VERSION 5.7 ;
BUSBITCHARS "[]" ;
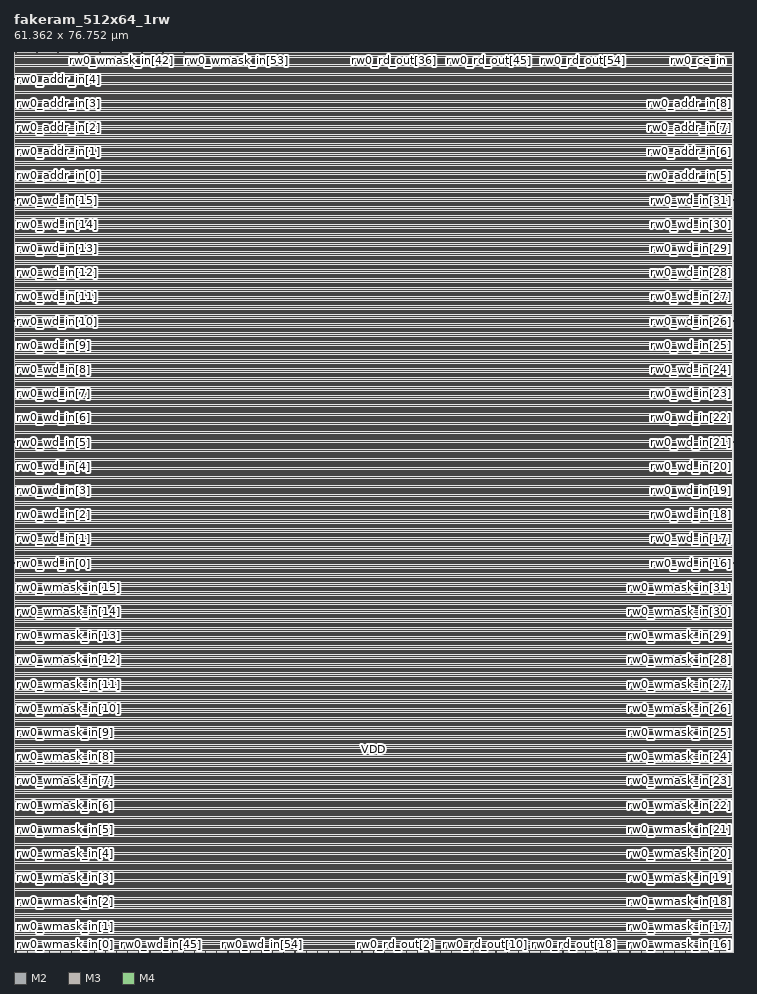
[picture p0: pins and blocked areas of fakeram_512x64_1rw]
MACRO fakeram_512x64_1rw
  FOREIGN fakeram_512x64_1rw 0 0 ;
  SYMMETRY X Y R90 ;
  SIZE 61.362 BY 76.752 ;
  CLASS BLOCK ;
  PIN rw0_wmask_in[0]
    DIRECTION INPUT ;
    USE SIGNAL ;
    SHAPE ABUTMENT ;
    PORT
      LAYER M2 ;
      RECT 0.000 0.138 0.036 0.150 ;
    END
  END rw0_wmask_in[0]
  PIN rw0_wmask_in[1]
    DIRECTION INPUT ;
    USE SIGNAL ;
    SHAPE ABUTMENT ;
    PORT
      LAYER M2 ;
      RECT 0.000 2.202 0.036 2.214 ;
    END
  END rw0_wmask_in[1]
  PIN rw0_wmask_in[2]
    DIRECTION INPUT ;
    USE SIGNAL ;
    SHAPE ABUTMENT ;
    PORT
      LAYER M2 ;
      RECT 0.000 4.266 0.036 4.278 ;
    END
  END rw0_wmask_in[2]
  PIN rw0_wmask_in[3]
    DIRECTION INPUT ;
    USE SIGNAL ;
    SHAPE ABUTMENT ;
    PORT
      LAYER M2 ;
      RECT 0.000 6.330 0.036 6.342 ;
    END
  END rw0_wmask_in[3]
  PIN rw0_wmask_in[4]
    DIRECTION INPUT ;
    USE SIGNAL ;
    SHAPE ABUTMENT ;
    PORT
      LAYER M2 ;
      RECT 0.000 8.394 0.036 8.406 ;
    END
  END rw0_wmask_in[4]
  PIN rw0_wmask_in[5]
    DIRECTION INPUT ;
    USE SIGNAL ;
    SHAPE ABUTMENT ;
    PORT
      LAYER M2 ;
      RECT 0.000 10.458 0.036 10.470 ;
    END
  END rw0_wmask_in[5]
  PIN rw0_wmask_in[6]
    DIRECTION INPUT ;
    USE SIGNAL ;
    SHAPE ABUTMENT ;
    PORT
      LAYER M2 ;
      RECT 0.000 12.522 0.036 12.534 ;
    END
  END rw0_wmask_in[6]
  PIN rw0_wmask_in[7]
    DIRECTION INPUT ;
    USE SIGNAL ;
    SHAPE ABUTMENT ;
    PORT
      LAYER M2 ;
      RECT 0.000 14.586 0.036 14.598 ;
    END
  END rw0_wmask_in[7]
  PIN rw0_wmask_in[8]
    DIRECTION INPUT ;
    USE SIGNAL ;
    SHAPE ABUTMENT ;
    PORT
      LAYER M2 ;
      RECT 0.000 16.650 0.036 16.662 ;
    END
  END rw0_wmask_in[8]
  PIN rw0_wmask_in[9]
    DIRECTION INPUT ;
    USE SIGNAL ;
    SHAPE ABUTMENT ;
    PORT
      LAYER M2 ;
      RECT 0.000 18.714 0.036 18.726 ;
    END
  END rw0_wmask_in[9]
  PIN rw0_wmask_in[10]
    DIRECTION INPUT ;
    USE SIGNAL ;
    SHAPE ABUTMENT ;
    PORT
      LAYER M2 ;
      RECT 0.000 20.778 0.036 20.790 ;
    END
  END rw0_wmask_in[10]
  PIN rw0_wmask_in[11]
    DIRECTION INPUT ;
    USE SIGNAL ;
    SHAPE ABUTMENT ;
    PORT
      LAYER M2 ;
      RECT 0.000 22.842 0.036 22.854 ;
    END
  END rw0_wmask_in[11]
  PIN rw0_wmask_in[12]
    DIRECTION INPUT ;
    USE SIGNAL ;
    SHAPE ABUTMENT ;
    PORT
      LAYER M2 ;
      RECT 0.000 24.906 0.036 24.918 ;
    END
  END rw0_wmask_in[12]
  PIN rw0_wmask_in[13]
    DIRECTION INPUT ;
    USE SIGNAL ;
    SHAPE ABUTMENT ;
    PORT
      LAYER M2 ;
      RECT 0.000 26.970 0.036 26.982 ;
    END
  END rw0_wmask_in[13]
  PIN rw0_wmask_in[14]
    DIRECTION INPUT ;
    USE SIGNAL ;
    SHAPE ABUTMENT ;
    PORT
      LAYER M2 ;
      RECT 0.000 29.034 0.036 29.046 ;
    END
  END rw0_wmask_in[14]
  PIN rw0_wmask_in[15]
    DIRECTION INPUT ;
    USE SIGNAL ;
    SHAPE ABUTMENT ;
    PORT
      LAYER M2 ;
      RECT 0.000 31.098 0.036 31.110 ;
    END
  END rw0_wmask_in[15]
  PIN rw0_wmask_in[16]
    DIRECTION INPUT ;
    USE SIGNAL ;
    SHAPE ABUTMENT ;
    PORT
      LAYER M2 ;
      RECT 61.326 0.138 61.362 0.150 ;
    END
  END rw0_wmask_in[16]
  PIN rw0_wmask_in[17]
    DIRECTION INPUT ;
    USE SIGNAL ;
    SHAPE ABUTMENT ;
    PORT
      LAYER M2 ;
      RECT 61.326 2.202 61.362 2.214 ;
    END
  END rw0_wmask_in[17]
  PIN rw0_wmask_in[18]
    DIRECTION INPUT ;
    USE SIGNAL ;
    SHAPE ABUTMENT ;
    PORT
      LAYER M2 ;
      RECT 61.326 4.266 61.362 4.278 ;
    END
  END rw0_wmask_in[18]
  PIN rw0_wmask_in[19]
    DIRECTION INPUT ;
    USE SIGNAL ;
    SHAPE ABUTMENT ;
    PORT
      LAYER M2 ;
      RECT 61.326 6.330 61.362 6.342 ;
    END
  END rw0_wmask_in[19]
  PIN rw0_wmask_in[20]
    DIRECTION INPUT ;
    USE SIGNAL ;
    SHAPE ABUTMENT ;
    PORT
      LAYER M2 ;
      RECT 61.326 8.394 61.362 8.406 ;
    END
  END rw0_wmask_in[20]
  PIN rw0_wmask_in[21]
    DIRECTION INPUT ;
    USE SIGNAL ;
    SHAPE ABUTMENT ;
    PORT
      LAYER M2 ;
      RECT 61.326 10.458 61.362 10.470 ;
    END
  END rw0_wmask_in[21]
  PIN rw0_wmask_in[22]
    DIRECTION INPUT ;
    USE SIGNAL ;
    SHAPE ABUTMENT ;
    PORT
      LAYER M2 ;
      RECT 61.326 12.522 61.362 12.534 ;
    END
  END rw0_wmask_in[22]
  PIN rw0_wmask_in[23]
    DIRECTION INPUT ;
    USE SIGNAL ;
    SHAPE ABUTMENT ;
    PORT
      LAYER M2 ;
      RECT 61.326 14.586 61.362 14.598 ;
    END
  END rw0_wmask_in[23]
  PIN rw0_wmask_in[24]
    DIRECTION INPUT ;
    USE SIGNAL ;
    SHAPE ABUTMENT ;
    PORT
      LAYER M2 ;
      RECT 61.326 16.650 61.362 16.662 ;
    END
  END rw0_wmask_in[24]
  PIN rw0_wmask_in[25]
    DIRECTION INPUT ;
    USE SIGNAL ;
    SHAPE ABUTMENT ;
    PORT
      LAYER M2 ;
      RECT 61.326 18.714 61.362 18.726 ;
    END
  END rw0_wmask_in[25]
  PIN rw0_wmask_in[26]
    DIRECTION INPUT ;
    USE SIGNAL ;
    SHAPE ABUTMENT ;
    PORT
      LAYER M2 ;
      RECT 61.326 20.778 61.362 20.790 ;
    END
  END rw0_wmask_in[26]
  PIN rw0_wmask_in[27]
    DIRECTION INPUT ;
    USE SIGNAL ;
    SHAPE ABUTMENT ;
    PORT
      LAYER M2 ;
      RECT 61.326 22.842 61.362 22.854 ;
    END
  END rw0_wmask_in[27]
  PIN rw0_wmask_in[28]
    DIRECTION INPUT ;
    USE SIGNAL ;
    SHAPE ABUTMENT ;
    PORT
      LAYER M2 ;
      RECT 61.326 24.906 61.362 24.918 ;
    END
  END rw0_wmask_in[28]
  PIN rw0_wmask_in[29]
    DIRECTION INPUT ;
    USE SIGNAL ;
    SHAPE ABUTMENT ;
    PORT
      LAYER M2 ;
      RECT 61.326 26.970 61.362 26.982 ;
    END
  END rw0_wmask_in[29]
  PIN rw0_wmask_in[30]
    DIRECTION INPUT ;
    USE SIGNAL ;
    SHAPE ABUTMENT ;
    PORT
      LAYER M2 ;
      RECT 61.326 29.034 61.362 29.046 ;
    END
  END rw0_wmask_in[30]
  PIN rw0_wmask_in[31]
    DIRECTION INPUT ;
    USE SIGNAL ;
    SHAPE ABUTMENT ;
    PORT
      LAYER M2 ;
      RECT 61.326 31.098 61.362 31.110 ;
    END
  END rw0_wmask_in[31]
  PIN rw0_wmask_in[32]
    DIRECTION INPUT ;
    USE SIGNAL ;
    SHAPE ABUTMENT ;
    PORT
      LAYER M3 ;
      RECT 0.161 76.710 0.175 76.752 ;
    END
  END rw0_wmask_in[32]
  PIN rw0_wmask_in[33]
    DIRECTION INPUT ;
    USE SIGNAL ;
    SHAPE ABUTMENT ;
    PORT
      LAYER M3 ;
      RECT 1.057 76.710 1.071 76.752 ;
    END
  END rw0_wmask_in[33]
  PIN rw0_wmask_in[34]
    DIRECTION INPUT ;
    USE SIGNAL ;
    SHAPE ABUTMENT ;
    PORT
      LAYER M3 ;
      RECT 1.953 76.710 1.967 76.752 ;
    END
  END rw0_wmask_in[34]
  PIN rw0_wmask_in[35]
    DIRECTION INPUT ;
    USE SIGNAL ;
    SHAPE ABUTMENT ;
    PORT
      LAYER M3 ;
      RECT 2.849 76.710 2.863 76.752 ;
    END
  END rw0_wmask_in[35]
  PIN rw0_wmask_in[36]
    DIRECTION INPUT ;
    USE SIGNAL ;
    SHAPE ABUTMENT ;
    PORT
      LAYER M3 ;
      RECT 3.745 76.710 3.759 76.752 ;
    END
  END rw0_wmask_in[36]
  PIN rw0_wmask_in[37]
    DIRECTION INPUT ;
    USE SIGNAL ;
    SHAPE ABUTMENT ;
    PORT
      LAYER M3 ;
      RECT 4.641 76.710 4.655 76.752 ;
    END
  END rw0_wmask_in[37]
  PIN rw0_wmask_in[38]
    DIRECTION INPUT ;
    USE SIGNAL ;
    SHAPE ABUTMENT ;
    PORT
      LAYER M3 ;
      RECT 5.537 76.710 5.551 76.752 ;
    END
  END rw0_wmask_in[38]
  PIN rw0_wmask_in[39]
    DIRECTION INPUT ;
    USE SIGNAL ;
    SHAPE ABUTMENT ;
    PORT
      LAYER M3 ;
      RECT 6.433 76.710 6.447 76.752 ;
    END
  END rw0_wmask_in[39]
  PIN rw0_wmask_in[40]
    DIRECTION INPUT ;
    USE SIGNAL ;
    SHAPE ABUTMENT ;
    PORT
      LAYER M3 ;
      RECT 7.329 76.710 7.343 76.752 ;
    END
  END rw0_wmask_in[40]
  PIN rw0_wmask_in[41]
    DIRECTION INPUT ;
    USE SIGNAL ;
    SHAPE ABUTMENT ;
    PORT
      LAYER M3 ;
      RECT 8.225 76.710 8.239 76.752 ;
    END
  END rw0_wmask_in[41]
  PIN rw0_wmask_in[42]
    DIRECTION INPUT ;
    USE SIGNAL ;
    SHAPE ABUTMENT ;
    PORT
      LAYER M3 ;
      RECT 9.121 76.710 9.135 76.752 ;
    END
  END rw0_wmask_in[42]
  PIN rw0_wmask_in[43]
    DIRECTION INPUT ;
    USE SIGNAL ;
    SHAPE ABUTMENT ;
    PORT
      LAYER M3 ;
      RECT 10.017 76.710 10.031 76.752 ;
    END
  END rw0_wmask_in[43]
  PIN rw0_wmask_in[44]
    DIRECTION INPUT ;
    USE SIGNAL ;
    SHAPE ABUTMENT ;
    PORT
      LAYER M3 ;
      RECT 10.913 76.710 10.927 76.752 ;
    END
  END rw0_wmask_in[44]
  PIN rw0_wmask_in[45]
    DIRECTION INPUT ;
    USE SIGNAL ;
    SHAPE ABUTMENT ;
    PORT
      LAYER M3 ;
      RECT 11.809 76.710 11.823 76.752 ;
    END
  END rw0_wmask_in[45]
  PIN rw0_wmask_in[46]
    DIRECTION INPUT ;
    USE SIGNAL ;
    SHAPE ABUTMENT ;
    PORT
      LAYER M3 ;
      RECT 12.705 76.710 12.719 76.752 ;
    END
  END rw0_wmask_in[46]
  PIN rw0_wmask_in[47]
    DIRECTION INPUT ;
    USE SIGNAL ;
    SHAPE ABUTMENT ;
    PORT
      LAYER M3 ;
      RECT 13.601 76.710 13.615 76.752 ;
    END
  END rw0_wmask_in[47]
  PIN rw0_wmask_in[48]
    DIRECTION INPUT ;
    USE SIGNAL ;
    SHAPE ABUTMENT ;
    PORT
      LAYER M3 ;
      RECT 14.497 76.710 14.511 76.752 ;
    END
  END rw0_wmask_in[48]
  PIN rw0_wmask_in[49]
    DIRECTION INPUT ;
    USE SIGNAL ;
    SHAPE ABUTMENT ;
    PORT
      LAYER M3 ;
      RECT 15.393 76.710 15.407 76.752 ;
    END
  END rw0_wmask_in[49]
  PIN rw0_wmask_in[50]
    DIRECTION INPUT ;
    USE SIGNAL ;
    SHAPE ABUTMENT ;
    PORT
      LAYER M3 ;
      RECT 16.289 76.710 16.303 76.752 ;
    END
  END rw0_wmask_in[50]
  PIN rw0_wmask_in[51]
    DIRECTION INPUT ;
    USE SIGNAL ;
    SHAPE ABUTMENT ;
    PORT
      LAYER M3 ;
      RECT 17.185 76.710 17.199 76.752 ;
    END
  END rw0_wmask_in[51]
  PIN rw0_wmask_in[52]
    DIRECTION INPUT ;
    USE SIGNAL ;
    SHAPE ABUTMENT ;
    PORT
      LAYER M3 ;
      RECT 18.081 76.710 18.095 76.752 ;
    END
  END rw0_wmask_in[52]
  PIN rw0_wmask_in[53]
    DIRECTION INPUT ;
    USE SIGNAL ;
    SHAPE ABUTMENT ;
    PORT
      LAYER M3 ;
      RECT 18.977 76.710 18.991 76.752 ;
    END
  END rw0_wmask_in[53]
  PIN rw0_wmask_in[54]
    DIRECTION INPUT ;
    USE SIGNAL ;
    SHAPE ABUTMENT ;
    PORT
      LAYER M3 ;
      RECT 19.873 76.710 19.887 76.752 ;
    END
  END rw0_wmask_in[54]
  PIN rw0_wmask_in[55]
    DIRECTION INPUT ;
    USE SIGNAL ;
    SHAPE ABUTMENT ;
    PORT
      LAYER M3 ;
      RECT 20.769 76.710 20.783 76.752 ;
    END
  END rw0_wmask_in[55]
  PIN rw0_wmask_in[56]
    DIRECTION INPUT ;
    USE SIGNAL ;
    SHAPE ABUTMENT ;
    PORT
      LAYER M3 ;
      RECT 21.665 76.710 21.679 76.752 ;
    END
  END rw0_wmask_in[56]
  PIN rw0_wmask_in[57]
    DIRECTION INPUT ;
    USE SIGNAL ;
    SHAPE ABUTMENT ;
    PORT
      LAYER M3 ;
      RECT 22.561 76.710 22.575 76.752 ;
    END
  END rw0_wmask_in[57]
  PIN rw0_wmask_in[58]
    DIRECTION INPUT ;
    USE SIGNAL ;
    SHAPE ABUTMENT ;
    PORT
      LAYER M3 ;
      RECT 23.457 76.710 23.471 76.752 ;
    END
  END rw0_wmask_in[58]
  PIN rw0_wmask_in[59]
    DIRECTION INPUT ;
    USE SIGNAL ;
    SHAPE ABUTMENT ;
    PORT
      LAYER M3 ;
      RECT 24.353 76.710 24.367 76.752 ;
    END
  END rw0_wmask_in[59]
  PIN rw0_wmask_in[60]
    DIRECTION INPUT ;
    USE SIGNAL ;
    SHAPE ABUTMENT ;
    PORT
      LAYER M3 ;
      RECT 25.249 76.710 25.263 76.752 ;
    END
  END rw0_wmask_in[60]
  PIN rw0_wmask_in[61]
    DIRECTION INPUT ;
    USE SIGNAL ;
    SHAPE ABUTMENT ;
    PORT
      LAYER M3 ;
      RECT 26.145 76.710 26.159 76.752 ;
    END
  END rw0_wmask_in[61]
  PIN rw0_wmask_in[62]
    DIRECTION INPUT ;
    USE SIGNAL ;
    SHAPE ABUTMENT ;
    PORT
      LAYER M3 ;
      RECT 27.041 76.710 27.055 76.752 ;
    END
  END rw0_wmask_in[62]
  PIN rw0_wmask_in[63]
    DIRECTION INPUT ;
    USE SIGNAL ;
    SHAPE ABUTMENT ;
    PORT
      LAYER M3 ;
      RECT 27.937 76.710 27.951 76.752 ;
    END
  END rw0_wmask_in[63]
  PIN rw0_wd_in[0]
    DIRECTION INPUT ;
    USE SIGNAL ;
    SHAPE ABUTMENT ;
    PORT
      LAYER M2 ;
      RECT 0.000 33.162 0.036 33.174 ;
    END
  END rw0_wd_in[0]
  PIN rw0_wd_in[1]
    DIRECTION INPUT ;
    USE SIGNAL ;
    SHAPE ABUTMENT ;
    PORT
      LAYER M2 ;
      RECT 0.000 35.226 0.036 35.238 ;
    END
  END rw0_wd_in[1]
  PIN rw0_wd_in[2]
    DIRECTION INPUT ;
    USE SIGNAL ;
    SHAPE ABUTMENT ;
    PORT
      LAYER M2 ;
      RECT 0.000 37.290 0.036 37.302 ;
    END
  END rw0_wd_in[2]
  PIN rw0_wd_in[3]
    DIRECTION INPUT ;
    USE SIGNAL ;
    SHAPE ABUTMENT ;
    PORT
      LAYER M2 ;
      RECT 0.000 39.354 0.036 39.366 ;
    END
  END rw0_wd_in[3]
  PIN rw0_wd_in[4]
    DIRECTION INPUT ;
    USE SIGNAL ;
    SHAPE ABUTMENT ;
    PORT
      LAYER M2 ;
      RECT 0.000 41.418 0.036 41.430 ;
    END
  END rw0_wd_in[4]
  PIN rw0_wd_in[5]
    DIRECTION INPUT ;
    USE SIGNAL ;
    SHAPE ABUTMENT ;
    PORT
      LAYER M2 ;
      RECT 0.000 43.482 0.036 43.494 ;
    END
  END rw0_wd_in[5]
  PIN rw0_wd_in[6]
    DIRECTION INPUT ;
    USE SIGNAL ;
    SHAPE ABUTMENT ;
    PORT
      LAYER M2 ;
      RECT 0.000 45.546 0.036 45.558 ;
    END
  END rw0_wd_in[6]
  PIN rw0_wd_in[7]
    DIRECTION INPUT ;
    USE SIGNAL ;
    SHAPE ABUTMENT ;
    PORT
      LAYER M2 ;
      RECT 0.000 47.610 0.036 47.622 ;
    END
  END rw0_wd_in[7]
  PIN rw0_wd_in[8]
    DIRECTION INPUT ;
    USE SIGNAL ;
    SHAPE ABUTMENT ;
    PORT
      LAYER M2 ;
      RECT 0.000 49.674 0.036 49.686 ;
    END
  END rw0_wd_in[8]
  PIN rw0_wd_in[9]
    DIRECTION INPUT ;
    USE SIGNAL ;
    SHAPE ABUTMENT ;
    PORT
      LAYER M2 ;
      RECT 0.000 51.738 0.036 51.750 ;
    END
  END rw0_wd_in[9]
  PIN rw0_wd_in[10]
    DIRECTION INPUT ;
    USE SIGNAL ;
    SHAPE ABUTMENT ;
    PORT
      LAYER M2 ;
      RECT 0.000 53.802 0.036 53.814 ;
    END
  END rw0_wd_in[10]
  PIN rw0_wd_in[11]
    DIRECTION INPUT ;
    USE SIGNAL ;
    SHAPE ABUTMENT ;
    PORT
      LAYER M2 ;
      RECT 0.000 55.866 0.036 55.878 ;
    END
  END rw0_wd_in[11]
  PIN rw0_wd_in[12]
    DIRECTION INPUT ;
    USE SIGNAL ;
    SHAPE ABUTMENT ;
    PORT
      LAYER M2 ;
      RECT 0.000 57.930 0.036 57.942 ;
    END
  END rw0_wd_in[12]
  PIN rw0_wd_in[13]
    DIRECTION INPUT ;
    USE SIGNAL ;
    SHAPE ABUTMENT ;
    PORT
      LAYER M2 ;
      RECT 0.000 59.994 0.036 60.006 ;
    END
  END rw0_wd_in[13]
  PIN rw0_wd_in[14]
    DIRECTION INPUT ;
    USE SIGNAL ;
    SHAPE ABUTMENT ;
    PORT
      LAYER M2 ;
      RECT 0.000 62.058 0.036 62.070 ;
    END
  END rw0_wd_in[14]
  PIN rw0_wd_in[15]
    DIRECTION INPUT ;
    USE SIGNAL ;
    SHAPE ABUTMENT ;
    PORT
      LAYER M2 ;
      RECT 0.000 64.122 0.036 64.134 ;
    END
  END rw0_wd_in[15]
  PIN rw0_wd_in[16]
    DIRECTION INPUT ;
    USE SIGNAL ;
    SHAPE ABUTMENT ;
    PORT
      LAYER M2 ;
      RECT 61.326 33.162 61.362 33.174 ;
    END
  END rw0_wd_in[16]
  PIN rw0_wd_in[17]
    DIRECTION INPUT ;
    USE SIGNAL ;
    SHAPE ABUTMENT ;
    PORT
      LAYER M2 ;
      RECT 61.326 35.226 61.362 35.238 ;
    END
  END rw0_wd_in[17]
  PIN rw0_wd_in[18]
    DIRECTION INPUT ;
    USE SIGNAL ;
    SHAPE ABUTMENT ;
    PORT
      LAYER M2 ;
      RECT 61.326 37.290 61.362 37.302 ;
    END
  END rw0_wd_in[18]
  PIN rw0_wd_in[19]
    DIRECTION INPUT ;
    USE SIGNAL ;
    SHAPE ABUTMENT ;
    PORT
      LAYER M2 ;
      RECT 61.326 39.354 61.362 39.366 ;
    END
  END rw0_wd_in[19]
  PIN rw0_wd_in[20]
    DIRECTION INPUT ;
    USE SIGNAL ;
    SHAPE ABUTMENT ;
    PORT
      LAYER M2 ;
      RECT 61.326 41.418 61.362 41.430 ;
    END
  END rw0_wd_in[20]
  PIN rw0_wd_in[21]
    DIRECTION INPUT ;
    USE SIGNAL ;
    SHAPE ABUTMENT ;
    PORT
      LAYER M2 ;
      RECT 61.326 43.482 61.362 43.494 ;
    END
  END rw0_wd_in[21]
  PIN rw0_wd_in[22]
    DIRECTION INPUT ;
    USE SIGNAL ;
    SHAPE ABUTMENT ;
    PORT
      LAYER M2 ;
      RECT 61.326 45.546 61.362 45.558 ;
    END
  END rw0_wd_in[22]
  PIN rw0_wd_in[23]
    DIRECTION INPUT ;
    USE SIGNAL ;
    SHAPE ABUTMENT ;
    PORT
      LAYER M2 ;
      RECT 61.326 47.610 61.362 47.622 ;
    END
  END rw0_wd_in[23]
  PIN rw0_wd_in[24]
    DIRECTION INPUT ;
    USE SIGNAL ;
    SHAPE ABUTMENT ;
    PORT
      LAYER M2 ;
      RECT 61.326 49.674 61.362 49.686 ;
    END
  END rw0_wd_in[24]
  PIN rw0_wd_in[25]
    DIRECTION INPUT ;
    USE SIGNAL ;
    SHAPE ABUTMENT ;
    PORT
      LAYER M2 ;
      RECT 61.326 51.738 61.362 51.750 ;
    END
  END rw0_wd_in[25]
  PIN rw0_wd_in[26]
    DIRECTION INPUT ;
    USE SIGNAL ;
    SHAPE ABUTMENT ;
    PORT
      LAYER M2 ;
      RECT 61.326 53.802 61.362 53.814 ;
    END
  END rw0_wd_in[26]
  PIN rw0_wd_in[27]
    DIRECTION INPUT ;
    USE SIGNAL ;
    SHAPE ABUTMENT ;
    PORT
      LAYER M2 ;
      RECT 61.326 55.866 61.362 55.878 ;
    END
  END rw0_wd_in[27]
  PIN rw0_wd_in[28]
    DIRECTION INPUT ;
    USE SIGNAL ;
    SHAPE ABUTMENT ;
    PORT
      LAYER M2 ;
      RECT 61.326 57.930 61.362 57.942 ;
    END
  END rw0_wd_in[28]
  PIN rw0_wd_in[29]
    DIRECTION INPUT ;
    USE SIGNAL ;
    SHAPE ABUTMENT ;
    PORT
      LAYER M2 ;
      RECT 61.326 59.994 61.362 60.006 ;
    END
  END rw0_wd_in[29]
  PIN rw0_wd_in[30]
    DIRECTION INPUT ;
    USE SIGNAL ;
    SHAPE ABUTMENT ;
    PORT
      LAYER M2 ;
      RECT 61.326 62.058 61.362 62.070 ;
    END
  END rw0_wd_in[30]
  PIN rw0_wd_in[31]
    DIRECTION INPUT ;
    USE SIGNAL ;
    SHAPE ABUTMENT ;
    PORT
      LAYER M2 ;
      RECT 61.326 64.122 61.362 64.134 ;
    END
  END rw0_wd_in[31]
  PIN rw0_wd_in[32]
    DIRECTION INPUT ;
    USE SIGNAL ;
    SHAPE ABUTMENT ;
    PORT
      LAYER M3 ;
      RECT 0.161 0.000 0.175 0.042 ;
    END
  END rw0_wd_in[32]
  PIN rw0_wd_in[33]
    DIRECTION INPUT ;
    USE SIGNAL ;
    SHAPE ABUTMENT ;
    PORT
      LAYER M3 ;
      RECT 1.113 0.000 1.127 0.042 ;
    END
  END rw0_wd_in[33]
  PIN rw0_wd_in[34]
    DIRECTION INPUT ;
    USE SIGNAL ;
    SHAPE ABUTMENT ;
    PORT
      LAYER M3 ;
      RECT 2.065 0.000 2.079 0.042 ;
    END
  END rw0_wd_in[34]
  PIN rw0_wd_in[35]
    DIRECTION INPUT ;
    USE SIGNAL ;
    SHAPE ABUTMENT ;
    PORT
      LAYER M3 ;
      RECT 3.017 0.000 3.031 0.042 ;
    END
  END rw0_wd_in[35]
  PIN rw0_wd_in[36]
    DIRECTION INPUT ;
    USE SIGNAL ;
    SHAPE ABUTMENT ;
    PORT
      LAYER M3 ;
      RECT 3.969 0.000 3.983 0.042 ;
    END
  END rw0_wd_in[36]
  PIN rw0_wd_in[37]
    DIRECTION INPUT ;
    USE SIGNAL ;
    SHAPE ABUTMENT ;
    PORT
      LAYER M3 ;
      RECT 4.921 0.000 4.935 0.042 ;
    END
  END rw0_wd_in[37]
  PIN rw0_wd_in[38]
    DIRECTION INPUT ;
    USE SIGNAL ;
    SHAPE ABUTMENT ;
    PORT
      LAYER M3 ;
      RECT 5.873 0.000 5.887 0.042 ;
    END
  END rw0_wd_in[38]
  PIN rw0_wd_in[39]
    DIRECTION INPUT ;
    USE SIGNAL ;
    SHAPE ABUTMENT ;
    PORT
      LAYER M3 ;
      RECT 6.825 0.000 6.839 0.042 ;
    END
  END rw0_wd_in[39]
  PIN rw0_wd_in[40]
    DIRECTION INPUT ;
    USE SIGNAL ;
    SHAPE ABUTMENT ;
    PORT
      LAYER M3 ;
      RECT 7.777 0.000 7.791 0.042 ;
    END
  END rw0_wd_in[40]
  PIN rw0_wd_in[41]
    DIRECTION INPUT ;
    USE SIGNAL ;
    SHAPE ABUTMENT ;
    PORT
      LAYER M3 ;
      RECT 8.729 0.000 8.743 0.042 ;
    END
  END rw0_wd_in[41]
  PIN rw0_wd_in[42]
    DIRECTION INPUT ;
    USE SIGNAL ;
    SHAPE ABUTMENT ;
    PORT
      LAYER M3 ;
      RECT 9.681 0.000 9.695 0.042 ;
    END
  END rw0_wd_in[42]
  PIN rw0_wd_in[43]
    DIRECTION INPUT ;
    USE SIGNAL ;
    SHAPE ABUTMENT ;
    PORT
      LAYER M3 ;
      RECT 10.633 0.000 10.647 0.042 ;
    END
  END rw0_wd_in[43]
  PIN rw0_wd_in[44]
    DIRECTION INPUT ;
    USE SIGNAL ;
    SHAPE ABUTMENT ;
    PORT
      LAYER M3 ;
      RECT 11.585 0.000 11.599 0.042 ;
    END
  END rw0_wd_in[44]
  PIN rw0_wd_in[45]
    DIRECTION INPUT ;
    USE SIGNAL ;
    SHAPE ABUTMENT ;
    PORT
      LAYER M3 ;
      RECT 12.537 0.000 12.551 0.042 ;
    END
  END rw0_wd_in[45]
  PIN rw0_wd_in[46]
    DIRECTION INPUT ;
    USE SIGNAL ;
    SHAPE ABUTMENT ;
    PORT
      LAYER M3 ;
      RECT 13.489 0.000 13.503 0.042 ;
    END
  END rw0_wd_in[46]
  PIN rw0_wd_in[47]
    DIRECTION INPUT ;
    USE SIGNAL ;
    SHAPE ABUTMENT ;
    PORT
      LAYER M3 ;
      RECT 14.441 0.000 14.455 0.042 ;
    END
  END rw0_wd_in[47]
  PIN rw0_wd_in[48]
    DIRECTION INPUT ;
    USE SIGNAL ;
    SHAPE ABUTMENT ;
    PORT
      LAYER M3 ;
      RECT 15.393 0.000 15.407 0.042 ;
    END
  END rw0_wd_in[48]
  PIN rw0_wd_in[49]
    DIRECTION INPUT ;
    USE SIGNAL ;
    SHAPE ABUTMENT ;
    PORT
      LAYER M3 ;
      RECT 16.345 0.000 16.359 0.042 ;
    END
  END rw0_wd_in[49]
  PIN rw0_wd_in[50]
    DIRECTION INPUT ;
    USE SIGNAL ;
    SHAPE ABUTMENT ;
    PORT
      LAYER M3 ;
      RECT 17.297 0.000 17.311 0.042 ;
    END
  END rw0_wd_in[50]
  PIN rw0_wd_in[51]
    DIRECTION INPUT ;
    USE SIGNAL ;
    SHAPE ABUTMENT ;
    PORT
      LAYER M3 ;
      RECT 18.249 0.000 18.263 0.042 ;
    END
  END rw0_wd_in[51]
  PIN rw0_wd_in[52]
    DIRECTION INPUT ;
    USE SIGNAL ;
    SHAPE ABUTMENT ;
    PORT
      LAYER M3 ;
      RECT 19.201 0.000 19.215 0.042 ;
    END
  END rw0_wd_in[52]
  PIN rw0_wd_in[53]
    DIRECTION INPUT ;
    USE SIGNAL ;
    SHAPE ABUTMENT ;
    PORT
      LAYER M3 ;
      RECT 20.153 0.000 20.167 0.042 ;
    END
  END rw0_wd_in[53]
  PIN rw0_wd_in[54]
    DIRECTION INPUT ;
    USE SIGNAL ;
    SHAPE ABUTMENT ;
    PORT
      LAYER M3 ;
      RECT 21.105 0.000 21.119 0.042 ;
    END
  END rw0_wd_in[54]
  PIN rw0_wd_in[55]
    DIRECTION INPUT ;
    USE SIGNAL ;
    SHAPE ABUTMENT ;
    PORT
      LAYER M3 ;
      RECT 22.057 0.000 22.071 0.042 ;
    END
  END rw0_wd_in[55]
  PIN rw0_wd_in[56]
    DIRECTION INPUT ;
    USE SIGNAL ;
    SHAPE ABUTMENT ;
    PORT
      LAYER M3 ;
      RECT 23.009 0.000 23.023 0.042 ;
    END
  END rw0_wd_in[56]
  PIN rw0_wd_in[57]
    DIRECTION INPUT ;
    USE SIGNAL ;
    SHAPE ABUTMENT ;
    PORT
      LAYER M3 ;
      RECT 23.961 0.000 23.975 0.042 ;
    END
  END rw0_wd_in[57]
  PIN rw0_wd_in[58]
    DIRECTION INPUT ;
    USE SIGNAL ;
    SHAPE ABUTMENT ;
    PORT
      LAYER M3 ;
      RECT 24.913 0.000 24.927 0.042 ;
    END
  END rw0_wd_in[58]
  PIN rw0_wd_in[59]
    DIRECTION INPUT ;
    USE SIGNAL ;
    SHAPE ABUTMENT ;
    PORT
      LAYER M3 ;
      RECT 25.865 0.000 25.879 0.042 ;
    END
  END rw0_wd_in[59]
  PIN rw0_wd_in[60]
    DIRECTION INPUT ;
    USE SIGNAL ;
    SHAPE ABUTMENT ;
    PORT
      LAYER M3 ;
      RECT 26.817 0.000 26.831 0.042 ;
    END
  END rw0_wd_in[60]
  PIN rw0_wd_in[61]
    DIRECTION INPUT ;
    USE SIGNAL ;
    SHAPE ABUTMENT ;
    PORT
      LAYER M3 ;
      RECT 27.769 0.000 27.783 0.042 ;
    END
  END rw0_wd_in[61]
  PIN rw0_wd_in[62]
    DIRECTION INPUT ;
    USE SIGNAL ;
    SHAPE ABUTMENT ;
    PORT
      LAYER M3 ;
      RECT 28.721 0.000 28.735 0.042 ;
    END
  END rw0_wd_in[62]
  PIN rw0_wd_in[63]
    DIRECTION INPUT ;
    USE SIGNAL ;
    SHAPE ABUTMENT ;
    PORT
      LAYER M3 ;
      RECT 29.673 0.000 29.687 0.042 ;
    END
  END rw0_wd_in[63]
  PIN rw0_rd_out[0]
    DIRECTION OUTPUT ;
    USE SIGNAL ;
    SHAPE ABUTMENT ;
    PORT
      LAYER M3 ;
      RECT 30.625 0.000 30.639 0.042 ;
    END
  END rw0_rd_out[0]
  PIN rw0_rd_out[1]
    DIRECTION OUTPUT ;
    USE SIGNAL ;
    SHAPE ABUTMENT ;
    PORT
      LAYER M3 ;
      RECT 31.577 0.000 31.591 0.042 ;
    END
  END rw0_rd_out[1]
  PIN rw0_rd_out[2]
    DIRECTION OUTPUT ;
    USE SIGNAL ;
    SHAPE ABUTMENT ;
    PORT
      LAYER M3 ;
      RECT 32.529 0.000 32.543 0.042 ;
    END
  END rw0_rd_out[2]
  PIN rw0_rd_out[3]
    DIRECTION OUTPUT ;
    USE SIGNAL ;
    SHAPE ABUTMENT ;
    PORT
      LAYER M3 ;
      RECT 33.481 0.000 33.495 0.042 ;
    END
  END rw0_rd_out[3]
  PIN rw0_rd_out[4]
    DIRECTION OUTPUT ;
    USE SIGNAL ;
    SHAPE ABUTMENT ;
    PORT
      LAYER M3 ;
      RECT 34.433 0.000 34.447 0.042 ;
    END
  END rw0_rd_out[4]
  PIN rw0_rd_out[5]
    DIRECTION OUTPUT ;
    USE SIGNAL ;
    SHAPE ABUTMENT ;
    PORT
      LAYER M3 ;
      RECT 35.385 0.000 35.399 0.042 ;
    END
  END rw0_rd_out[5]
  PIN rw0_rd_out[6]
    DIRECTION OUTPUT ;
    USE SIGNAL ;
    SHAPE ABUTMENT ;
    PORT
      LAYER M3 ;
      RECT 36.337 0.000 36.351 0.042 ;
    END
  END rw0_rd_out[6]
  PIN rw0_rd_out[7]
    DIRECTION OUTPUT ;
    USE SIGNAL ;
    SHAPE ABUTMENT ;
    PORT
      LAYER M3 ;
      RECT 37.289 0.000 37.303 0.042 ;
    END
  END rw0_rd_out[7]
  PIN rw0_rd_out[8]
    DIRECTION OUTPUT ;
    USE SIGNAL ;
    SHAPE ABUTMENT ;
    PORT
      LAYER M3 ;
      RECT 38.241 0.000 38.255 0.042 ;
    END
  END rw0_rd_out[8]
  PIN rw0_rd_out[9]
    DIRECTION OUTPUT ;
    USE SIGNAL ;
    SHAPE ABUTMENT ;
    PORT
      LAYER M3 ;
      RECT 39.193 0.000 39.207 0.042 ;
    END
  END rw0_rd_out[9]
  PIN rw0_rd_out[10]
    DIRECTION OUTPUT ;
    USE SIGNAL ;
    SHAPE ABUTMENT ;
    PORT
      LAYER M3 ;
      RECT 40.145 0.000 40.159 0.042 ;
    END
  END rw0_rd_out[10]
  PIN rw0_rd_out[11]
    DIRECTION OUTPUT ;
    USE SIGNAL ;
    SHAPE ABUTMENT ;
    PORT
      LAYER M3 ;
      RECT 41.097 0.000 41.111 0.042 ;
    END
  END rw0_rd_out[11]
  PIN rw0_rd_out[12]
    DIRECTION OUTPUT ;
    USE SIGNAL ;
    SHAPE ABUTMENT ;
    PORT
      LAYER M3 ;
      RECT 42.049 0.000 42.063 0.042 ;
    END
  END rw0_rd_out[12]
  PIN rw0_rd_out[13]
    DIRECTION OUTPUT ;
    USE SIGNAL ;
    SHAPE ABUTMENT ;
    PORT
      LAYER M3 ;
      RECT 43.001 0.000 43.015 0.042 ;
    END
  END rw0_rd_out[13]
  PIN rw0_rd_out[14]
    DIRECTION OUTPUT ;
    USE SIGNAL ;
    SHAPE ABUTMENT ;
    PORT
      LAYER M3 ;
      RECT 43.953 0.000 43.967 0.042 ;
    END
  END rw0_rd_out[14]
  PIN rw0_rd_out[15]
    DIRECTION OUTPUT ;
    USE SIGNAL ;
    SHAPE ABUTMENT ;
    PORT
      LAYER M3 ;
      RECT 44.905 0.000 44.919 0.042 ;
    END
  END rw0_rd_out[15]
  PIN rw0_rd_out[16]
    DIRECTION OUTPUT ;
    USE SIGNAL ;
    SHAPE ABUTMENT ;
    PORT
      LAYER M3 ;
      RECT 45.857 0.000 45.871 0.042 ;
    END
  END rw0_rd_out[16]
  PIN rw0_rd_out[17]
    DIRECTION OUTPUT ;
    USE SIGNAL ;
    SHAPE ABUTMENT ;
    PORT
      LAYER M3 ;
      RECT 46.809 0.000 46.823 0.042 ;
    END
  END rw0_rd_out[17]
  PIN rw0_rd_out[18]
    DIRECTION OUTPUT ;
    USE SIGNAL ;
    SHAPE ABUTMENT ;
    PORT
      LAYER M3 ;
      RECT 47.761 0.000 47.775 0.042 ;
    END
  END rw0_rd_out[18]
  PIN rw0_rd_out[19]
    DIRECTION OUTPUT ;
    USE SIGNAL ;
    SHAPE ABUTMENT ;
    PORT
      LAYER M3 ;
      RECT 48.713 0.000 48.727 0.042 ;
    END
  END rw0_rd_out[19]
  PIN rw0_rd_out[20]
    DIRECTION OUTPUT ;
    USE SIGNAL ;
    SHAPE ABUTMENT ;
    PORT
      LAYER M3 ;
      RECT 49.665 0.000 49.679 0.042 ;
    END
  END rw0_rd_out[20]
  PIN rw0_rd_out[21]
    DIRECTION OUTPUT ;
    USE SIGNAL ;
    SHAPE ABUTMENT ;
    PORT
      LAYER M3 ;
      RECT 50.617 0.000 50.631 0.042 ;
    END
  END rw0_rd_out[21]
  PIN rw0_rd_out[22]
    DIRECTION OUTPUT ;
    USE SIGNAL ;
    SHAPE ABUTMENT ;
    PORT
      LAYER M3 ;
      RECT 51.569 0.000 51.583 0.042 ;
    END
  END rw0_rd_out[22]
  PIN rw0_rd_out[23]
    DIRECTION OUTPUT ;
    USE SIGNAL ;
    SHAPE ABUTMENT ;
    PORT
      LAYER M3 ;
      RECT 52.521 0.000 52.535 0.042 ;
    END
  END rw0_rd_out[23]
  PIN rw0_rd_out[24]
    DIRECTION OUTPUT ;
    USE SIGNAL ;
    SHAPE ABUTMENT ;
    PORT
      LAYER M3 ;
      RECT 53.473 0.000 53.487 0.042 ;
    END
  END rw0_rd_out[24]
  PIN rw0_rd_out[25]
    DIRECTION OUTPUT ;
    USE SIGNAL ;
    SHAPE ABUTMENT ;
    PORT
      LAYER M3 ;
      RECT 54.425 0.000 54.439 0.042 ;
    END
  END rw0_rd_out[25]
  PIN rw0_rd_out[26]
    DIRECTION OUTPUT ;
    USE SIGNAL ;
    SHAPE ABUTMENT ;
    PORT
      LAYER M3 ;
      RECT 55.377 0.000 55.391 0.042 ;
    END
  END rw0_rd_out[26]
  PIN rw0_rd_out[27]
    DIRECTION OUTPUT ;
    USE SIGNAL ;
    SHAPE ABUTMENT ;
    PORT
      LAYER M3 ;
      RECT 56.329 0.000 56.343 0.042 ;
    END
  END rw0_rd_out[27]
  PIN rw0_rd_out[28]
    DIRECTION OUTPUT ;
    USE SIGNAL ;
    SHAPE ABUTMENT ;
    PORT
      LAYER M3 ;
      RECT 57.281 0.000 57.295 0.042 ;
    END
  END rw0_rd_out[28]
  PIN rw0_rd_out[29]
    DIRECTION OUTPUT ;
    USE SIGNAL ;
    SHAPE ABUTMENT ;
    PORT
      LAYER M3 ;
      RECT 58.233 0.000 58.247 0.042 ;
    END
  END rw0_rd_out[29]
  PIN rw0_rd_out[30]
    DIRECTION OUTPUT ;
    USE SIGNAL ;
    SHAPE ABUTMENT ;
    PORT
      LAYER M3 ;
      RECT 59.185 0.000 59.199 0.042 ;
    END
  END rw0_rd_out[30]
  PIN rw0_rd_out[31]
    DIRECTION OUTPUT ;
    USE SIGNAL ;
    SHAPE ABUTMENT ;
    PORT
      LAYER M3 ;
      RECT 60.137 0.000 60.151 0.042 ;
    END
  END rw0_rd_out[31]
  PIN rw0_rd_out[32]
    DIRECTION OUTPUT ;
    USE SIGNAL ;
    SHAPE ABUTMENT ;
    PORT
      LAYER M3 ;
      RECT 28.833 76.710 28.847 76.752 ;
    END
  END rw0_rd_out[32]
  PIN rw0_rd_out[33]
    DIRECTION OUTPUT ;
    USE SIGNAL ;
    SHAPE ABUTMENT ;
    PORT
      LAYER M3 ;
      RECT 29.729 76.710 29.743 76.752 ;
    END
  END rw0_rd_out[33]
  PIN rw0_rd_out[34]
    DIRECTION OUTPUT ;
    USE SIGNAL ;
    SHAPE ABUTMENT ;
    PORT
      LAYER M3 ;
      RECT 30.625 76.710 30.639 76.752 ;
    END
  END rw0_rd_out[34]
  PIN rw0_rd_out[35]
    DIRECTION OUTPUT ;
    USE SIGNAL ;
    SHAPE ABUTMENT ;
    PORT
      LAYER M3 ;
      RECT 31.521 76.710 31.535 76.752 ;
    END
  END rw0_rd_out[35]
  PIN rw0_rd_out[36]
    DIRECTION OUTPUT ;
    USE SIGNAL ;
    SHAPE ABUTMENT ;
    PORT
      LAYER M3 ;
      RECT 32.417 76.710 32.431 76.752 ;
    END
  END rw0_rd_out[36]
  PIN rw0_rd_out[37]
    DIRECTION OUTPUT ;
    USE SIGNAL ;
    SHAPE ABUTMENT ;
    PORT
      LAYER M3 ;
      RECT 33.313 76.710 33.327 76.752 ;
    END
  END rw0_rd_out[37]
  PIN rw0_rd_out[38]
    DIRECTION OUTPUT ;
    USE SIGNAL ;
    SHAPE ABUTMENT ;
    PORT
      LAYER M3 ;
      RECT 34.209 76.710 34.223 76.752 ;
    END
  END rw0_rd_out[38]
  PIN rw0_rd_out[39]
    DIRECTION OUTPUT ;
    USE SIGNAL ;
    SHAPE ABUTMENT ;
    PORT
      LAYER M3 ;
      RECT 35.105 76.710 35.119 76.752 ;
    END
  END rw0_rd_out[39]
  PIN rw0_rd_out[40]
    DIRECTION OUTPUT ;
    USE SIGNAL ;
    SHAPE ABUTMENT ;
    PORT
      LAYER M3 ;
      RECT 36.001 76.710 36.015 76.752 ;
    END
  END rw0_rd_out[40]
  PIN rw0_rd_out[41]
    DIRECTION OUTPUT ;
    USE SIGNAL ;
    SHAPE ABUTMENT ;
    PORT
      LAYER M3 ;
      RECT 36.897 76.710 36.911 76.752 ;
    END
  END rw0_rd_out[41]
  PIN rw0_rd_out[42]
    DIRECTION OUTPUT ;
    USE SIGNAL ;
    SHAPE ABUTMENT ;
    PORT
      LAYER M3 ;
      RECT 37.793 76.710 37.807 76.752 ;
    END
  END rw0_rd_out[42]
  PIN rw0_rd_out[43]
    DIRECTION OUTPUT ;
    USE SIGNAL ;
    SHAPE ABUTMENT ;
    PORT
      LAYER M3 ;
      RECT 38.689 76.710 38.703 76.752 ;
    END
  END rw0_rd_out[43]
  PIN rw0_rd_out[44]
    DIRECTION OUTPUT ;
    USE SIGNAL ;
    SHAPE ABUTMENT ;
    PORT
      LAYER M3 ;
      RECT 39.585 76.710 39.599 76.752 ;
    END
  END rw0_rd_out[44]
  PIN rw0_rd_out[45]
    DIRECTION OUTPUT ;
    USE SIGNAL ;
    SHAPE ABUTMENT ;
    PORT
      LAYER M3 ;
      RECT 40.481 76.710 40.495 76.752 ;
    END
  END rw0_rd_out[45]
  PIN rw0_rd_out[46]
    DIRECTION OUTPUT ;
    USE SIGNAL ;
    SHAPE ABUTMENT ;
    PORT
      LAYER M3 ;
      RECT 41.377 76.710 41.391 76.752 ;
    END
  END rw0_rd_out[46]
  PIN rw0_rd_out[47]
    DIRECTION OUTPUT ;
    USE SIGNAL ;
    SHAPE ABUTMENT ;
    PORT
      LAYER M3 ;
      RECT 42.273 76.710 42.287 76.752 ;
    END
  END rw0_rd_out[47]
  PIN rw0_rd_out[48]
    DIRECTION OUTPUT ;
    USE SIGNAL ;
    SHAPE ABUTMENT ;
    PORT
      LAYER M3 ;
      RECT 43.169 76.710 43.183 76.752 ;
    END
  END rw0_rd_out[48]
  PIN rw0_rd_out[49]
    DIRECTION OUTPUT ;
    USE SIGNAL ;
    SHAPE ABUTMENT ;
    PORT
      LAYER M3 ;
      RECT 44.065 76.710 44.079 76.752 ;
    END
  END rw0_rd_out[49]
  PIN rw0_rd_out[50]
    DIRECTION OUTPUT ;
    USE SIGNAL ;
    SHAPE ABUTMENT ;
    PORT
      LAYER M3 ;
      RECT 44.961 76.710 44.975 76.752 ;
    END
  END rw0_rd_out[50]
  PIN rw0_rd_out[51]
    DIRECTION OUTPUT ;
    USE SIGNAL ;
    SHAPE ABUTMENT ;
    PORT
      LAYER M3 ;
      RECT 45.857 76.710 45.871 76.752 ;
    END
  END rw0_rd_out[51]
  PIN rw0_rd_out[52]
    DIRECTION OUTPUT ;
    USE SIGNAL ;
    SHAPE ABUTMENT ;
    PORT
      LAYER M3 ;
      RECT 46.753 76.710 46.767 76.752 ;
    END
  END rw0_rd_out[52]
  PIN rw0_rd_out[53]
    DIRECTION OUTPUT ;
    USE SIGNAL ;
    SHAPE ABUTMENT ;
    PORT
      LAYER M3 ;
      RECT 47.649 76.710 47.663 76.752 ;
    END
  END rw0_rd_out[53]
  PIN rw0_rd_out[54]
    DIRECTION OUTPUT ;
    USE SIGNAL ;
    SHAPE ABUTMENT ;
    PORT
      LAYER M3 ;
      RECT 48.545 76.710 48.559 76.752 ;
    END
  END rw0_rd_out[54]
  PIN rw0_rd_out[55]
    DIRECTION OUTPUT ;
    USE SIGNAL ;
    SHAPE ABUTMENT ;
    PORT
      LAYER M3 ;
      RECT 49.441 76.710 49.455 76.752 ;
    END
  END rw0_rd_out[55]
  PIN rw0_rd_out[56]
    DIRECTION OUTPUT ;
    USE SIGNAL ;
    SHAPE ABUTMENT ;
    PORT
      LAYER M3 ;
      RECT 50.337 76.710 50.351 76.752 ;
    END
  END rw0_rd_out[56]
  PIN rw0_rd_out[57]
    DIRECTION OUTPUT ;
    USE SIGNAL ;
    SHAPE ABUTMENT ;
    PORT
      LAYER M3 ;
      RECT 51.233 76.710 51.247 76.752 ;
    END
  END rw0_rd_out[57]
  PIN rw0_rd_out[58]
    DIRECTION OUTPUT ;
    USE SIGNAL ;
    SHAPE ABUTMENT ;
    PORT
      LAYER M3 ;
      RECT 52.129 76.710 52.143 76.752 ;
    END
  END rw0_rd_out[58]
  PIN rw0_rd_out[59]
    DIRECTION OUTPUT ;
    USE SIGNAL ;
    SHAPE ABUTMENT ;
    PORT
      LAYER M3 ;
      RECT 53.025 76.710 53.039 76.752 ;
    END
  END rw0_rd_out[59]
  PIN rw0_rd_out[60]
    DIRECTION OUTPUT ;
    USE SIGNAL ;
    SHAPE ABUTMENT ;
    PORT
      LAYER M3 ;
      RECT 53.921 76.710 53.935 76.752 ;
    END
  END rw0_rd_out[60]
  PIN rw0_rd_out[61]
    DIRECTION OUTPUT ;
    USE SIGNAL ;
    SHAPE ABUTMENT ;
    PORT
      LAYER M3 ;
      RECT 54.817 76.710 54.831 76.752 ;
    END
  END rw0_rd_out[61]
  PIN rw0_rd_out[62]
    DIRECTION OUTPUT ;
    USE SIGNAL ;
    SHAPE ABUTMENT ;
    PORT
      LAYER M3 ;
      RECT 55.713 76.710 55.727 76.752 ;
    END
  END rw0_rd_out[62]
  PIN rw0_rd_out[63]
    DIRECTION OUTPUT ;
    USE SIGNAL ;
    SHAPE ABUTMENT ;
    PORT
      LAYER M3 ;
      RECT 56.609 76.710 56.623 76.752 ;
    END
  END rw0_rd_out[63]
  PIN rw0_addr_in[0]
    DIRECTION INPUT ;
    USE SIGNAL ;
    SHAPE ABUTMENT ;
    PORT
      LAYER M2 ;
      RECT 0.000 66.186 0.036 66.198 ;
    END
  END rw0_addr_in[0]
  PIN rw0_addr_in[1]
    DIRECTION INPUT ;
    USE SIGNAL ;
    SHAPE ABUTMENT ;
    PORT
      LAYER M2 ;
      RECT 0.000 68.250 0.036 68.262 ;
    END
  END rw0_addr_in[1]
  PIN rw0_addr_in[2]
    DIRECTION INPUT ;
    USE SIGNAL ;
    SHAPE ABUTMENT ;
    PORT
      LAYER M2 ;
      RECT 0.000 70.314 0.036 70.326 ;
    END
  END rw0_addr_in[2]
  PIN rw0_addr_in[3]
    DIRECTION INPUT ;
    USE SIGNAL ;
    SHAPE ABUTMENT ;
    PORT
      LAYER M2 ;
      RECT 0.000 72.378 0.036 72.390 ;
    END
  END rw0_addr_in[3]
  PIN rw0_addr_in[4]
    DIRECTION INPUT ;
    USE SIGNAL ;
    SHAPE ABUTMENT ;
    PORT
      LAYER M2 ;
      RECT 0.000 74.442 0.036 74.454 ;
    END
  END rw0_addr_in[4]
  PIN rw0_addr_in[5]
    DIRECTION INPUT ;
    USE SIGNAL ;
    SHAPE ABUTMENT ;
    PORT
      LAYER M2 ;
      RECT 61.326 66.186 61.362 66.198 ;
    END
  END rw0_addr_in[5]
  PIN rw0_addr_in[6]
    DIRECTION INPUT ;
    USE SIGNAL ;
    SHAPE ABUTMENT ;
    PORT
      LAYER M2 ;
      RECT 61.326 68.250 61.362 68.262 ;
    END
  END rw0_addr_in[6]
  PIN rw0_addr_in[7]
    DIRECTION INPUT ;
    USE SIGNAL ;
    SHAPE ABUTMENT ;
    PORT
      LAYER M2 ;
      RECT 61.326 70.314 61.362 70.326 ;
    END
  END rw0_addr_in[7]
  PIN rw0_addr_in[8]
    DIRECTION INPUT ;
    USE SIGNAL ;
    SHAPE ABUTMENT ;
    PORT
      LAYER M2 ;
      RECT 61.326 72.378 61.362 72.390 ;
    END
  END rw0_addr_in[8]
  PIN rw0_we_in
    DIRECTION INPUT ;
    USE SIGNAL ;
    SHAPE ABUTMENT ;
    PORT
      LAYER M3 ;
      RECT 57.505 76.710 57.519 76.752 ;
    END
  END rw0_we_in
  PIN rw0_ce_in
    DIRECTION INPUT ;
    USE SIGNAL ;
    SHAPE ABUTMENT ;
    PORT
      LAYER M3 ;
      RECT 58.401 76.710 58.415 76.752 ;
    END
  END rw0_ce_in
  PIN rw0_clk
    DIRECTION INPUT ;
    USE SIGNAL ;
    SHAPE ABUTMENT ;
    PORT
      LAYER M3 ;
      RECT 59.297 76.710 59.311 76.752 ;
    END
  END rw0_clk
  PIN VSS
    DIRECTION INOUT ;
    USE GROUND ;
    PORT
      LAYER M4 ;
      RECT 0.168 0.120 61.194 0.168 ;
      RECT 0.168 0.504 61.194 0.552 ;
      RECT 0.168 0.888 61.194 0.936 ;
      RECT 0.168 1.272 61.194 1.320 ;
      RECT 0.168 1.656 61.194 1.704 ;
      RECT 0.168 2.040 61.194 2.088 ;
      RECT 0.168 2.424 61.194 2.472 ;
      RECT 0.168 2.808 61.194 2.856 ;
      RECT 0.168 3.192 61.194 3.240 ;
      RECT 0.168 3.576 61.194 3.624 ;
      RECT 0.168 3.960 61.194 4.008 ;
      RECT 0.168 4.344 61.194 4.392 ;
      RECT 0.168 4.728 61.194 4.776 ;
      RECT 0.168 5.112 61.194 5.160 ;
      RECT 0.168 5.496 61.194 5.544 ;
      RECT 0.168 5.880 61.194 5.928 ;
      RECT 0.168 6.264 61.194 6.312 ;
      RECT 0.168 6.648 61.194 6.696 ;
      RECT 0.168 7.032 61.194 7.080 ;
      RECT 0.168 7.416 61.194 7.464 ;
      RECT 0.168 7.800 61.194 7.848 ;
      RECT 0.168 8.184 61.194 8.232 ;
      RECT 0.168 8.568 61.194 8.616 ;
      RECT 0.168 8.952 61.194 9.000 ;
      RECT 0.168 9.336 61.194 9.384 ;
      RECT 0.168 9.720 61.194 9.768 ;
      RECT 0.168 10.104 61.194 10.152 ;
      RECT 0.168 10.488 61.194 10.536 ;
      RECT 0.168 10.872 61.194 10.920 ;
      RECT 0.168 11.256 61.194 11.304 ;
      RECT 0.168 11.640 61.194 11.688 ;
      RECT 0.168 12.024 61.194 12.072 ;
      RECT 0.168 12.408 61.194 12.456 ;
      RECT 0.168 12.792 61.194 12.840 ;
      RECT 0.168 13.176 61.194 13.224 ;
      RECT 0.168 13.560 61.194 13.608 ;
      RECT 0.168 13.944 61.194 13.992 ;
      RECT 0.168 14.328 61.194 14.376 ;
      RECT 0.168 14.712 61.194 14.760 ;
      RECT 0.168 15.096 61.194 15.144 ;
      RECT 0.168 15.480 61.194 15.528 ;
      RECT 0.168 15.864 61.194 15.912 ;
      RECT 0.168 16.248 61.194 16.296 ;
      RECT 0.168 16.632 61.194 16.680 ;
      RECT 0.168 17.016 61.194 17.064 ;
      RECT 0.168 17.400 61.194 17.448 ;
      RECT 0.168 17.784 61.194 17.832 ;
      RECT 0.168 18.168 61.194 18.216 ;
      RECT 0.168 18.552 61.194 18.600 ;
      RECT 0.168 18.936 61.194 18.984 ;
      RECT 0.168 19.320 61.194 19.368 ;
      RECT 0.168 19.704 61.194 19.752 ;
      RECT 0.168 20.088 61.194 20.136 ;
      RECT 0.168 20.472 61.194 20.520 ;
      RECT 0.168 20.856 61.194 20.904 ;
      RECT 0.168 21.240 61.194 21.288 ;
      RECT 0.168 21.624 61.194 21.672 ;
      RECT 0.168 22.008 61.194 22.056 ;
      RECT 0.168 22.392 61.194 22.440 ;
      RECT 0.168 22.776 61.194 22.824 ;
      RECT 0.168 23.160 61.194 23.208 ;
      RECT 0.168 23.544 61.194 23.592 ;
      RECT 0.168 23.928 61.194 23.976 ;
      RECT 0.168 24.312 61.194 24.360 ;
      RECT 0.168 24.696 61.194 24.744 ;
      RECT 0.168 25.080 61.194 25.128 ;
      RECT 0.168 25.464 61.194 25.512 ;
      RECT 0.168 25.848 61.194 25.896 ;
      RECT 0.168 26.232 61.194 26.280 ;
      RECT 0.168 26.616 61.194 26.664 ;
      RECT 0.168 27.000 61.194 27.048 ;
      RECT 0.168 27.384 61.194 27.432 ;
      RECT 0.168 27.768 61.194 27.816 ;
      RECT 0.168 28.152 61.194 28.200 ;
      RECT 0.168 28.536 61.194 28.584 ;
      RECT 0.168 28.920 61.194 28.968 ;
      RECT 0.168 29.304 61.194 29.352 ;
      RECT 0.168 29.688 61.194 29.736 ;
      RECT 0.168 30.072 61.194 30.120 ;
      RECT 0.168 30.456 61.194 30.504 ;
      RECT 0.168 30.840 61.194 30.888 ;
      RECT 0.168 31.224 61.194 31.272 ;
      RECT 0.168 31.608 61.194 31.656 ;
      RECT 0.168 31.992 61.194 32.040 ;
      RECT 0.168 32.376 61.194 32.424 ;
      RECT 0.168 32.760 61.194 32.808 ;
      RECT 0.168 33.144 61.194 33.192 ;
      RECT 0.168 33.528 61.194 33.576 ;
      RECT 0.168 33.912 61.194 33.960 ;
      RECT 0.168 34.296 61.194 34.344 ;
      RECT 0.168 34.680 61.194 34.728 ;
      RECT 0.168 35.064 61.194 35.112 ;
      RECT 0.168 35.448 61.194 35.496 ;
      RECT 0.168 35.832 61.194 35.880 ;
      RECT 0.168 36.216 61.194 36.264 ;
      RECT 0.168 36.600 61.194 36.648 ;
      RECT 0.168 36.984 61.194 37.032 ;
      RECT 0.168 37.368 61.194 37.416 ;
      RECT 0.168 37.752 61.194 37.800 ;
      RECT 0.168 38.136 61.194 38.184 ;
      RECT 0.168 38.520 61.194 38.568 ;
      RECT 0.168 38.904 61.194 38.952 ;
      RECT 0.168 39.288 61.194 39.336 ;
      RECT 0.168 39.672 61.194 39.720 ;
      RECT 0.168 40.056 61.194 40.104 ;
      RECT 0.168 40.440 61.194 40.488 ;
      RECT 0.168 40.824 61.194 40.872 ;
      RECT 0.168 41.208 61.194 41.256 ;
      RECT 0.168 41.592 61.194 41.640 ;
      RECT 0.168 41.976 61.194 42.024 ;
      RECT 0.168 42.360 61.194 42.408 ;
      RECT 0.168 42.744 61.194 42.792 ;
      RECT 0.168 43.128 61.194 43.176 ;
      RECT 0.168 43.512 61.194 43.560 ;
      RECT 0.168 43.896 61.194 43.944 ;
      RECT 0.168 44.280 61.194 44.328 ;
      RECT 0.168 44.664 61.194 44.712 ;
      RECT 0.168 45.048 61.194 45.096 ;
      RECT 0.168 45.432 61.194 45.480 ;
      RECT 0.168 45.816 61.194 45.864 ;
      RECT 0.168 46.200 61.194 46.248 ;
      RECT 0.168 46.584 61.194 46.632 ;
      RECT 0.168 46.968 61.194 47.016 ;
      RECT 0.168 47.352 61.194 47.400 ;
      RECT 0.168 47.736 61.194 47.784 ;
      RECT 0.168 48.120 61.194 48.168 ;
      RECT 0.168 48.504 61.194 48.552 ;
      RECT 0.168 48.888 61.194 48.936 ;
      RECT 0.168 49.272 61.194 49.320 ;
      RECT 0.168 49.656 61.194 49.704 ;
      RECT 0.168 50.040 61.194 50.088 ;
      RECT 0.168 50.424 61.194 50.472 ;
      RECT 0.168 50.808 61.194 50.856 ;
      RECT 0.168 51.192 61.194 51.240 ;
      RECT 0.168 51.576 61.194 51.624 ;
      RECT 0.168 51.960 61.194 52.008 ;
      RECT 0.168 52.344 61.194 52.392 ;
      RECT 0.168 52.728 61.194 52.776 ;
      RECT 0.168 53.112 61.194 53.160 ;
      RECT 0.168 53.496 61.194 53.544 ;
      RECT 0.168 53.880 61.194 53.928 ;
      RECT 0.168 54.264 61.194 54.312 ;
      RECT 0.168 54.648 61.194 54.696 ;
      RECT 0.168 55.032 61.194 55.080 ;
      RECT 0.168 55.416 61.194 55.464 ;
      RECT 0.168 55.800 61.194 55.848 ;
      RECT 0.168 56.184 61.194 56.232 ;
      RECT 0.168 56.568 61.194 56.616 ;
      RECT 0.168 56.952 61.194 57.000 ;
      RECT 0.168 57.336 61.194 57.384 ;
      RECT 0.168 57.720 61.194 57.768 ;
      RECT 0.168 58.104 61.194 58.152 ;
      RECT 0.168 58.488 61.194 58.536 ;
      RECT 0.168 58.872 61.194 58.920 ;
      RECT 0.168 59.256 61.194 59.304 ;
      RECT 0.168 59.640 61.194 59.688 ;
      RECT 0.168 60.024 61.194 60.072 ;
      RECT 0.168 60.408 61.194 60.456 ;
      RECT 0.168 60.792 61.194 60.840 ;
      RECT 0.168 61.176 61.194 61.224 ;
      RECT 0.168 61.560 61.194 61.608 ;
      RECT 0.168 61.944 61.194 61.992 ;
      RECT 0.168 62.328 61.194 62.376 ;
      RECT 0.168 62.712 61.194 62.760 ;
      RECT 0.168 63.096 61.194 63.144 ;
      RECT 0.168 63.480 61.194 63.528 ;
      RECT 0.168 63.864 61.194 63.912 ;
      RECT 0.168 64.248 61.194 64.296 ;
      RECT 0.168 64.632 61.194 64.680 ;
      RECT 0.168 65.016 61.194 65.064 ;
      RECT 0.168 65.400 61.194 65.448 ;
      RECT 0.168 65.784 61.194 65.832 ;
      RECT 0.168 66.168 61.194 66.216 ;
      RECT 0.168 66.552 61.194 66.600 ;
      RECT 0.168 66.936 61.194 66.984 ;
      RECT 0.168 67.320 61.194 67.368 ;
      RECT 0.168 67.704 61.194 67.752 ;
      RECT 0.168 68.088 61.194 68.136 ;
      RECT 0.168 68.472 61.194 68.520 ;
      RECT 0.168 68.856 61.194 68.904 ;
      RECT 0.168 69.240 61.194 69.288 ;
      RECT 0.168 69.624 61.194 69.672 ;
      RECT 0.168 70.008 61.194 70.056 ;
      RECT 0.168 70.392 61.194 70.440 ;
      RECT 0.168 70.776 61.194 70.824 ;
      RECT 0.168 71.160 61.194 71.208 ;
      RECT 0.168 71.544 61.194 71.592 ;
      RECT 0.168 71.928 61.194 71.976 ;
      RECT 0.168 72.312 61.194 72.360 ;
      RECT 0.168 72.696 61.194 72.744 ;
      RECT 0.168 73.080 61.194 73.128 ;
      RECT 0.168 73.464 61.194 73.512 ;
      RECT 0.168 73.848 61.194 73.896 ;
      RECT 0.168 74.232 61.194 74.280 ;
      RECT 0.168 74.616 61.194 74.664 ;
      RECT 0.168 75.000 61.194 75.048 ;
      RECT 0.168 75.384 61.194 75.432 ;
      RECT 0.168 75.768 61.194 75.816 ;
      RECT 0.168 76.152 61.194 76.200 ;
      RECT 0.168 76.536 61.194 76.584 ;
    END
  END VSS
  PIN VDD
    DIRECTION INOUT ;
    USE POWER ;
    PORT
      LAYER M4 ;
      RECT 0.168 0.312 61.194 0.360 ;
      RECT 0.168 0.696 61.194 0.744 ;
      RECT 0.168 1.080 61.194 1.128 ;
      RECT 0.168 1.464 61.194 1.512 ;
      RECT 0.168 1.848 61.194 1.896 ;
      RECT 0.168 2.232 61.194 2.280 ;
      RECT 0.168 2.616 61.194 2.664 ;
      RECT 0.168 3.000 61.194 3.048 ;
      RECT 0.168 3.384 61.194 3.432 ;
      RECT 0.168 3.768 61.194 3.816 ;
      RECT 0.168 4.152 61.194 4.200 ;
      RECT 0.168 4.536 61.194 4.584 ;
      RECT 0.168 4.920 61.194 4.968 ;
      RECT 0.168 5.304 61.194 5.352 ;
      RECT 0.168 5.688 61.194 5.736 ;
      RECT 0.168 6.072 61.194 6.120 ;
      RECT 0.168 6.456 61.194 6.504 ;
      RECT 0.168 6.840 61.194 6.888 ;
      RECT 0.168 7.224 61.194 7.272 ;
      RECT 0.168 7.608 61.194 7.656 ;
      RECT 0.168 7.992 61.194 8.040 ;
      RECT 0.168 8.376 61.194 8.424 ;
      RECT 0.168 8.760 61.194 8.808 ;
      RECT 0.168 9.144 61.194 9.192 ;
      RECT 0.168 9.528 61.194 9.576 ;
      RECT 0.168 9.912 61.194 9.960 ;
      RECT 0.168 10.296 61.194 10.344 ;
      RECT 0.168 10.680 61.194 10.728 ;
      RECT 0.168 11.064 61.194 11.112 ;
      RECT 0.168 11.448 61.194 11.496 ;
      RECT 0.168 11.832 61.194 11.880 ;
      RECT 0.168 12.216 61.194 12.264 ;
      RECT 0.168 12.600 61.194 12.648 ;
      RECT 0.168 12.984 61.194 13.032 ;
      RECT 0.168 13.368 61.194 13.416 ;
      RECT 0.168 13.752 61.194 13.800 ;
      RECT 0.168 14.136 61.194 14.184 ;
      RECT 0.168 14.520 61.194 14.568 ;
      RECT 0.168 14.904 61.194 14.952 ;
      RECT 0.168 15.288 61.194 15.336 ;
      RECT 0.168 15.672 61.194 15.720 ;
      RECT 0.168 16.056 61.194 16.104 ;
      RECT 0.168 16.440 61.194 16.488 ;
      RECT 0.168 16.824 61.194 16.872 ;
      RECT 0.168 17.208 61.194 17.256 ;
      RECT 0.168 17.592 61.194 17.640 ;
      RECT 0.168 17.976 61.194 18.024 ;
      RECT 0.168 18.360 61.194 18.408 ;
      RECT 0.168 18.744 61.194 18.792 ;
      RECT 0.168 19.128 61.194 19.176 ;
      RECT 0.168 19.512 61.194 19.560 ;
      RECT 0.168 19.896 61.194 19.944 ;
      RECT 0.168 20.280 61.194 20.328 ;
      RECT 0.168 20.664 61.194 20.712 ;
      RECT 0.168 21.048 61.194 21.096 ;
      RECT 0.168 21.432 61.194 21.480 ;
      RECT 0.168 21.816 61.194 21.864 ;
      RECT 0.168 22.200 61.194 22.248 ;
      RECT 0.168 22.584 61.194 22.632 ;
      RECT 0.168 22.968 61.194 23.016 ;
      RECT 0.168 23.352 61.194 23.400 ;
      RECT 0.168 23.736 61.194 23.784 ;
      RECT 0.168 24.120 61.194 24.168 ;
      RECT 0.168 24.504 61.194 24.552 ;
      RECT 0.168 24.888 61.194 24.936 ;
      RECT 0.168 25.272 61.194 25.320 ;
      RECT 0.168 25.656 61.194 25.704 ;
      RECT 0.168 26.040 61.194 26.088 ;
      RECT 0.168 26.424 61.194 26.472 ;
      RECT 0.168 26.808 61.194 26.856 ;
      RECT 0.168 27.192 61.194 27.240 ;
      RECT 0.168 27.576 61.194 27.624 ;
      RECT 0.168 27.960 61.194 28.008 ;
      RECT 0.168 28.344 61.194 28.392 ;
      RECT 0.168 28.728 61.194 28.776 ;
      RECT 0.168 29.112 61.194 29.160 ;
      RECT 0.168 29.496 61.194 29.544 ;
      RECT 0.168 29.880 61.194 29.928 ;
      RECT 0.168 30.264 61.194 30.312 ;
      RECT 0.168 30.648 61.194 30.696 ;
      RECT 0.168 31.032 61.194 31.080 ;
      RECT 0.168 31.416 61.194 31.464 ;
      RECT 0.168 31.800 61.194 31.848 ;
      RECT 0.168 32.184 61.194 32.232 ;
      RECT 0.168 32.568 61.194 32.616 ;
      RECT 0.168 32.952 61.194 33.000 ;
      RECT 0.168 33.336 61.194 33.384 ;
      RECT 0.168 33.720 61.194 33.768 ;
      RECT 0.168 34.104 61.194 34.152 ;
      RECT 0.168 34.488 61.194 34.536 ;
      RECT 0.168 34.872 61.194 34.920 ;
      RECT 0.168 35.256 61.194 35.304 ;
      RECT 0.168 35.640 61.194 35.688 ;
      RECT 0.168 36.024 61.194 36.072 ;
      RECT 0.168 36.408 61.194 36.456 ;
      RECT 0.168 36.792 61.194 36.840 ;
      RECT 0.168 37.176 61.194 37.224 ;
      RECT 0.168 37.560 61.194 37.608 ;
      RECT 0.168 37.944 61.194 37.992 ;
      RECT 0.168 38.328 61.194 38.376 ;
      RECT 0.168 38.712 61.194 38.760 ;
      RECT 0.168 39.096 61.194 39.144 ;
      RECT 0.168 39.480 61.194 39.528 ;
      RECT 0.168 39.864 61.194 39.912 ;
      RECT 0.168 40.248 61.194 40.296 ;
      RECT 0.168 40.632 61.194 40.680 ;
      RECT 0.168 41.016 61.194 41.064 ;
      RECT 0.168 41.400 61.194 41.448 ;
      RECT 0.168 41.784 61.194 41.832 ;
      RECT 0.168 42.168 61.194 42.216 ;
      RECT 0.168 42.552 61.194 42.600 ;
      RECT 0.168 42.936 61.194 42.984 ;
      RECT 0.168 43.320 61.194 43.368 ;
      RECT 0.168 43.704 61.194 43.752 ;
      RECT 0.168 44.088 61.194 44.136 ;
      RECT 0.168 44.472 61.194 44.520 ;
      RECT 0.168 44.856 61.194 44.904 ;
      RECT 0.168 45.240 61.194 45.288 ;
      RECT 0.168 45.624 61.194 45.672 ;
      RECT 0.168 46.008 61.194 46.056 ;
      RECT 0.168 46.392 61.194 46.440 ;
      RECT 0.168 46.776 61.194 46.824 ;
      RECT 0.168 47.160 61.194 47.208 ;
      RECT 0.168 47.544 61.194 47.592 ;
      RECT 0.168 47.928 61.194 47.976 ;
      RECT 0.168 48.312 61.194 48.360 ;
      RECT 0.168 48.696 61.194 48.744 ;
      RECT 0.168 49.080 61.194 49.128 ;
      RECT 0.168 49.464 61.194 49.512 ;
      RECT 0.168 49.848 61.194 49.896 ;
      RECT 0.168 50.232 61.194 50.280 ;
      RECT 0.168 50.616 61.194 50.664 ;
      RECT 0.168 51.000 61.194 51.048 ;
      RECT 0.168 51.384 61.194 51.432 ;
      RECT 0.168 51.768 61.194 51.816 ;
      RECT 0.168 52.152 61.194 52.200 ;
      RECT 0.168 52.536 61.194 52.584 ;
      RECT 0.168 52.920 61.194 52.968 ;
      RECT 0.168 53.304 61.194 53.352 ;
      RECT 0.168 53.688 61.194 53.736 ;
      RECT 0.168 54.072 61.194 54.120 ;
      RECT 0.168 54.456 61.194 54.504 ;
      RECT 0.168 54.840 61.194 54.888 ;
      RECT 0.168 55.224 61.194 55.272 ;
      RECT 0.168 55.608 61.194 55.656 ;
      RECT 0.168 55.992 61.194 56.040 ;
      RECT 0.168 56.376 61.194 56.424 ;
      RECT 0.168 56.760 61.194 56.808 ;
      RECT 0.168 57.144 61.194 57.192 ;
      RECT 0.168 57.528 61.194 57.576 ;
      RECT 0.168 57.912 61.194 57.960 ;
      RECT 0.168 58.296 61.194 58.344 ;
      RECT 0.168 58.680 61.194 58.728 ;
      RECT 0.168 59.064 61.194 59.112 ;
      RECT 0.168 59.448 61.194 59.496 ;
      RECT 0.168 59.832 61.194 59.880 ;
      RECT 0.168 60.216 61.194 60.264 ;
      RECT 0.168 60.600 61.194 60.648 ;
      RECT 0.168 60.984 61.194 61.032 ;
      RECT 0.168 61.368 61.194 61.416 ;
      RECT 0.168 61.752 61.194 61.800 ;
      RECT 0.168 62.136 61.194 62.184 ;
      RECT 0.168 62.520 61.194 62.568 ;
      RECT 0.168 62.904 61.194 62.952 ;
      RECT 0.168 63.288 61.194 63.336 ;
      RECT 0.168 63.672 61.194 63.720 ;
      RECT 0.168 64.056 61.194 64.104 ;
      RECT 0.168 64.440 61.194 64.488 ;
      RECT 0.168 64.824 61.194 64.872 ;
      RECT 0.168 65.208 61.194 65.256 ;
      RECT 0.168 65.592 61.194 65.640 ;
      RECT 0.168 65.976 61.194 66.024 ;
      RECT 0.168 66.360 61.194 66.408 ;
      RECT 0.168 66.744 61.194 66.792 ;
      RECT 0.168 67.128 61.194 67.176 ;
      RECT 0.168 67.512 61.194 67.560 ;
      RECT 0.168 67.896 61.194 67.944 ;
      RECT 0.168 68.280 61.194 68.328 ;
      RECT 0.168 68.664 61.194 68.712 ;
      RECT 0.168 69.048 61.194 69.096 ;
      RECT 0.168 69.432 61.194 69.480 ;
      RECT 0.168 69.816 61.194 69.864 ;
      RECT 0.168 70.200 61.194 70.248 ;
      RECT 0.168 70.584 61.194 70.632 ;
      RECT 0.168 70.968 61.194 71.016 ;
      RECT 0.168 71.352 61.194 71.400 ;
      RECT 0.168 71.736 61.194 71.784 ;
      RECT 0.168 72.120 61.194 72.168 ;
      RECT 0.168 72.504 61.194 72.552 ;
      RECT 0.168 72.888 61.194 72.936 ;
      RECT 0.168 73.272 61.194 73.320 ;
      RECT 0.168 73.656 61.194 73.704 ;
      RECT 0.168 74.040 61.194 74.088 ;
      RECT 0.168 74.424 61.194 74.472 ;
      RECT 0.168 74.808 61.194 74.856 ;
      RECT 0.168 75.192 61.194 75.240 ;
      RECT 0.168 75.576 61.194 75.624 ;
      RECT 0.168 75.960 61.194 76.008 ;
      RECT 0.168 76.344 61.194 76.392 ;
    END
  END VDD
  OBS
    LAYER M1 ;
    RECT 0 0 61.362 76.752 ;
    LAYER M2 ;
    RECT 0 0 61.362 76.752 ;
    LAYER M3 ;
    RECT 0 0 61.362 76.752 ;
    LAYER M4 ;
    RECT 0 0 61.362 76.752 ;
  END
END fakeram_512x64_1rw

END LIBRARY
